VERSION 5.8 ;
BUSBITCHARS "[]" ;
DIVIDERCHAR "/" ;
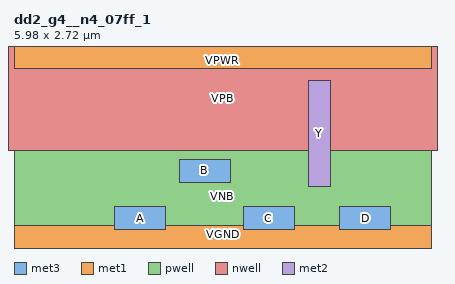
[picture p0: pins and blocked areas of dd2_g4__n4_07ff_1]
MACRO dd2_g4__n4_07ff_1
  CLASS CORE ;
  ORIGIN 0 0 ;
  SIZE 5.980 BY 2.720 ;
  SYMMETRY X Y ;
  SITE unithd ;
  PIN A
    DIRECTION INPUT ;
    USE SIGNAL ;
    ANTENNAGATEAREA 0.213000 ;
    PORT
      LAYER met3 ;
        RECT 1.445 0.175 2.175 0.505 ;
    END
  END A
  PIN B
    DIRECTION INPUT ;
    USE SIGNAL ;
    ANTENNAGATEAREA 0.213000 ;
    PORT
      LAYER met3 ;
        RECT 2.365 0.855 3.095 1.185 ;
    END
  END B
  PIN C
    DIRECTION INPUT ;
    USE SIGNAL ;
    ANTENNAGATEAREA 0.213000 ;
    PORT
      LAYER met3 ;
        RECT 3.285 0.175 4.015 0.505 ;
    END
  END C
  PIN D
    DIRECTION INPUT ;
    USE SIGNAL ;
    ANTENNAGATEAREA 0.213000 ;
    PORT
      LAYER met3 ;
        RECT 4.665 0.175 5.395 0.505 ;
    END
  END D
  PIN VGND
    DIRECTION INOUT ;
    USE GROUND ;
    SHAPE ABUTMENT ;
    PORT
      LAYER met1 ;
        RECT 0.000 -0.240 5.980 0.240 ;
    END
  END VGND
  PIN VNB
    DIRECTION INOUT ;
    USE GROUND ;
    PORT
      LAYER pwell ;
        RECT 0.000 0.000 5.980 1.305 ;
    END
  END VNB
  PIN VPB
    DIRECTION INOUT ;
    USE POWER ;
    PORT
      LAYER nwell ;
        RECT -0.190 1.305 6.170 2.910 ;
    END
  END VPB
  PIN VPWR
    DIRECTION INOUT ;
    USE POWER ;
    SHAPE ABUTMENT ;
    PORT
      LAYER met1 ;
        RECT 0.000 2.480 5.980 2.960 ;
    END
  END VPWR
  PIN Y
    DIRECTION OUTPUT ;
    USE SIGNAL ;
    ANTENNADIFFAREA 1.452600 ;
    PORT
      LAYER met2 ;
        RECT 4.210 0.790 4.530 2.305 ;
    END
  END Y
  OBS
    LAYER li1 ;
      RECT 0.000 -0.085 5.980 0.085 ;
      RECT 2.905 0.085 3.075 0.565 ;
      RECT 0.525 0.255 0.855 0.710 ;
      RECT 3.745 0.255 4.075 0.710 ;
      RECT 5.125 0.255 5.455 0.710 ;
      RECT 1.525 0.380 1.695 1.075 ;
      RECT 1.445 1.075 1.775 1.245 ;
      RECT 2.445 0.380 2.615 1.075 ;
      RECT 2.365 1.075 2.695 1.245 ;
      RECT 3.365 0.380 3.535 1.075 ;
      RECT 3.285 1.075 3.615 1.245 ;
      RECT 4.745 0.380 4.915 1.075 ;
      RECT 4.665 1.075 4.995 1.245 ;
      RECT 0.985 1.505 1.315 2.465 ;
      RECT 2.825 1.505 3.155 2.465 ;
      RECT 4.205 1.505 4.535 2.465 ;
      RECT 1.985 1.495 2.155 2.635 ;
      RECT 5.205 1.495 5.375 2.635 ;
      RECT 0.000 2.635 5.980 2.805 ;
    LAYER met1 ;
      RECT 0.525 0.380 0.855 0.710 ;
      RECT 1.465 0.380 1.755 0.710 ;
      RECT 2.385 0.380 2.675 0.710 ;
      RECT 3.305 0.380 3.595 0.710 ;
      RECT 3.745 0.380 4.075 0.710 ;
      RECT 4.685 0.380 4.975 0.710 ;
      RECT 0.990 0.790 1.310 0.850 ;
      RECT 2.830 0.790 3.150 0.850 ;
      RECT 0.985 0.850 3.155 0.990 ;
      RECT 0.990 0.990 1.310 1.050 ;
      RECT 2.830 0.990 3.150 1.050 ;
      RECT 5.125 0.380 5.455 0.710 ;
      RECT 4.210 0.790 4.530 0.850 ;
      RECT 5.130 0.710 5.450 0.850 ;
      RECT 4.205 0.850 5.455 0.990 ;
      RECT 4.210 0.990 4.530 1.050 ;
      RECT 5.130 0.990 5.450 1.050 ;
      RECT 0.530 1.230 0.850 1.290 ;
      RECT 3.750 1.230 4.070 1.290 ;
      RECT 0.525 1.290 4.075 1.430 ;
      RECT 0.530 1.430 0.850 1.490 ;
      RECT 3.750 1.430 4.070 1.490 ;
      RECT 0.985 2.010 1.315 2.340 ;
      RECT 2.825 2.010 3.155 2.340 ;
      RECT 4.205 2.010 4.535 2.340 ;
    LAYER met2 ;
      RECT 1.470 0.155 1.750 0.210 ;
      RECT 1.450 0.210 1.770 0.675 ;
      RECT 3.310 0.155 3.590 0.210 ;
      RECT 3.290 0.210 3.610 0.675 ;
      RECT 4.690 0.155 4.970 0.210 ;
      RECT 4.670 0.210 4.990 0.675 ;
      RECT 5.130 0.415 5.450 1.050 ;
      RECT 2.370 0.415 2.690 1.150 ;
      RECT 2.390 1.150 2.670 1.205 ;
      RECT 0.530 0.415 0.850 1.490 ;
      RECT 3.750 0.415 4.070 1.490 ;
      RECT 0.990 0.790 1.310 2.305 ;
      RECT 2.830 0.790 3.150 2.305 ;
  END
END dd2_g4__n4_07ff_1
END LIBRARY
